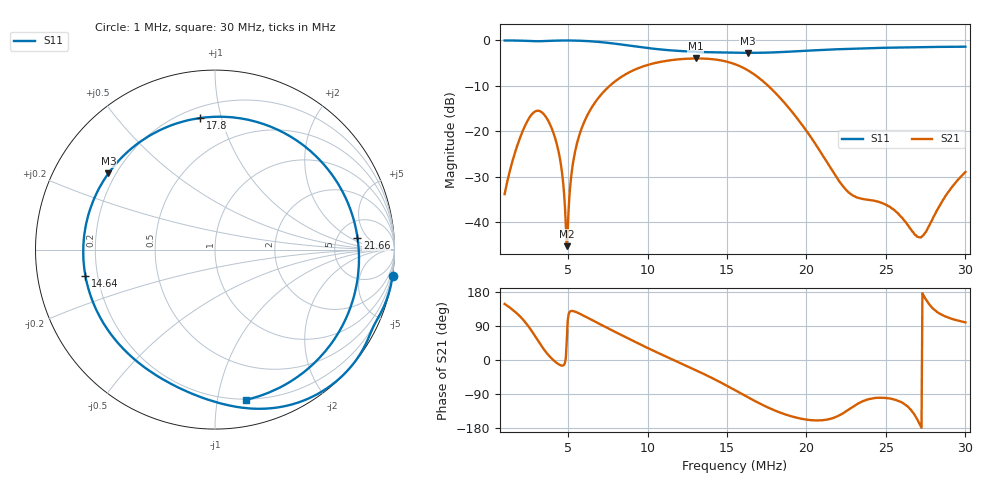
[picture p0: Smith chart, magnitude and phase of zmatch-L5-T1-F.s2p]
# HZ S RI R 50
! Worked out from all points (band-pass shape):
!   505 points, 1 MHz to 30 MHz, reference 50 ohm
!   highest |S21| = -3.96 dB at 13.03 MHz (marker M1); lowest = -45.3 dB at 4.913 MHz (marker M2)
!   |S21| within 3 dB of the highest: 8.871 MHz to 16.49 MHz (7.62 MHz wide, 60.1 % of centre)
!   lowest |S11| = -2.7 dB at 16.31 MHz (marker M3), VSWR 6.41, Z = 8.58 + j15.6 ohm
!   |S11| at or under -10 dB: nowhere
!   S12 and S22 are empty: the file has one direction only
!   S11 on the Smith chart (normalised r, x): 1 MHz: -0, -13; 14.64 MHz: 0.15, -0.10; 17.8 MHz: 0.27, +0.86; 21.66 MHz: 7.77, +2.86; 30 MHz: 0.19, -1.21
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1000000  0.9897 -0.1478  -0.0172 0.0108  0 0  0 0
2208340  0.9394 -0.3213  -0.0265 0.1042  0 0  0 0
3244060  0.8752 -0.4446  0.1237 0.1106  0 0  0 0
4337320  0.8028 -0.5913  0.0655 -0.0109  0 0  0 0
4625020  0.7744 -0.6313  0.0327 -0.00869  0 0  0 0
4912720  0.7421 -0.6698  0.00338 0.00426  0 0  0 0
5315500  0.691 -0.7205  -0.0291 0.0357  0 0  0 0
5833360  0.6156 -0.7781  -0.053 0.0919  0 0  0 0
6926620  0.4321 -0.8615  -0.0257 0.2345  0 0  0 0
8537740  0.1504 -0.8807  0.1965 0.3674  0 0  0 0
1.066672e7  -0.1774 -0.7813  0.545 0.183  0 0  0 0
1.302586e7  -0.5327 -0.5293  0.5663 -0.285  0 0  0 0
1.463698e7  -0.7217 -0.1476  0.3009 -0.5222  0 0  0 0
1.550008e7  -0.7179 0.1438  0.0992 -0.5392  0 0  0 0
1.630564e7  -0.5939 0.4246  -0.067 -0.4649  0 0  0 0
1.780168e7  -0.083 0.7331  -0.186 -0.2251  0 0  0 0
2.033344e7  0.6765 0.3813  -0.0776 -0.0299  0 0  0 0
2.165686e7  0.7938 0.0672  -0.0323 -0.0161  0 0  0 0
2.28652e7  0.7911 -0.183  -0.0114 -0.0164  0 0  0 0
2.51668e7  0.6443 -0.5287  -0.00288 -0.0147  0 0  0 0
2.723824e7  0.4488 -0.7165  -0.00686 -0.000173  0 0  0 0
3.000016e7  0.1712 -0.837  -0.00571 0.0352  0 0  0 0
